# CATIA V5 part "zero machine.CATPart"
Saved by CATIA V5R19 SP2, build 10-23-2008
Part number: zero machine
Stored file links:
  Z:\fausse table rondelle-20220905T211342Z-001\fausse table rondelle\zero machine.CATPart

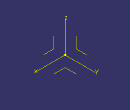
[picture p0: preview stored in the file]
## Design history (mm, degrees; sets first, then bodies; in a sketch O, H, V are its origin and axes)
AxisSystem1: origin (0, 0, 0), X (1, 0, 0), Y (0, 1, 0), Z (0, 0, 1)
Body1 (main body)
